VERSION 5.7 ;
  NOWIREEXTENSIONATPIN ON ;
  DIVIDERCHAR "/" ;
  BUSBITCHARS "[]" ;
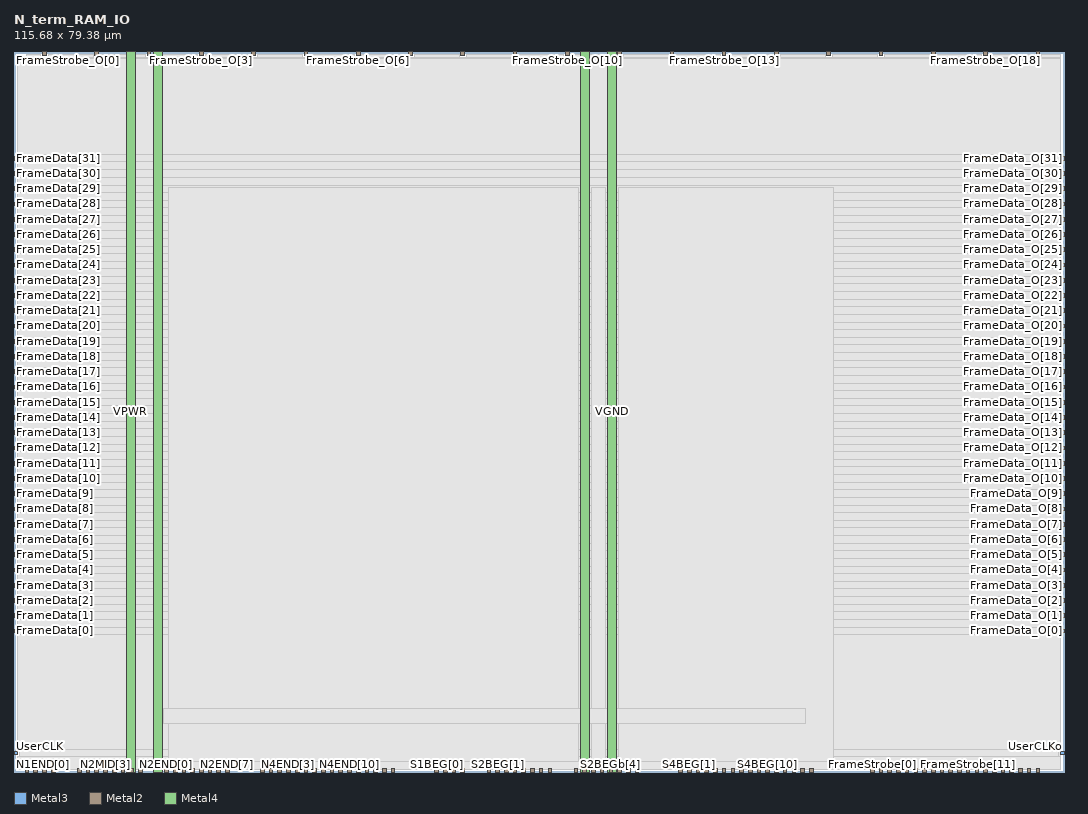
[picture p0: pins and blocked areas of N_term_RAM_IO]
MACRO N_term_RAM_IO
  CLASS BLOCK ;
  FOREIGN N_term_RAM_IO ;
  ORIGIN 0.000 0.000 ;
  SIZE 115.680 BY 79.380 ;
  PIN FrameData[0]
    DIRECTION INPUT ;
    USE SIGNAL ;
    ANTENNAGATEAREA 0.180700 ;
    PORT
      LAYER Metal3 ;
        RECT 0.000 15.340 0.400 15.740 ;
    END
  END FrameData[0]
  PIN FrameData[10]
    DIRECTION INPUT ;
    USE SIGNAL ;
    ANTENNAGATEAREA 0.180700 ;
    PORT
      LAYER Metal3 ;
        RECT 0.000 32.140 0.400 32.540 ;
    END
  END FrameData[10]
  PIN FrameData[11]
    DIRECTION INPUT ;
    USE SIGNAL ;
    ANTENNAGATEAREA 0.180700 ;
    PORT
      LAYER Metal3 ;
        RECT 0.000 33.820 0.400 34.220 ;
    END
  END FrameData[11]
  PIN FrameData[12]
    DIRECTION INPUT ;
    USE SIGNAL ;
    ANTENNAGATEAREA 0.180700 ;
    PORT
      LAYER Metal3 ;
        RECT 0.000 35.500 0.400 35.900 ;
    END
  END FrameData[12]
  PIN FrameData[13]
    DIRECTION INPUT ;
    USE SIGNAL ;
    ANTENNAGATEAREA 0.180700 ;
    PORT
      LAYER Metal3 ;
        RECT 0.000 37.180 0.400 37.580 ;
    END
  END FrameData[13]
  PIN FrameData[14]
    DIRECTION INPUT ;
    USE SIGNAL ;
    ANTENNAGATEAREA 0.180700 ;
    PORT
      LAYER Metal3 ;
        RECT 0.000 38.860 0.400 39.260 ;
    END
  END FrameData[14]
  PIN FrameData[15]
    DIRECTION INPUT ;
    USE SIGNAL ;
    ANTENNAGATEAREA 0.180700 ;
    PORT
      LAYER Metal3 ;
        RECT 0.000 40.540 0.400 40.940 ;
    END
  END FrameData[15]
  PIN FrameData[16]
    DIRECTION INPUT ;
    USE SIGNAL ;
    ANTENNAGATEAREA 0.180700 ;
    PORT
      LAYER Metal3 ;
        RECT 0.000 42.220 0.400 42.620 ;
    END
  END FrameData[16]
  PIN FrameData[17]
    DIRECTION INPUT ;
    USE SIGNAL ;
    ANTENNAGATEAREA 0.180700 ;
    PORT
      LAYER Metal3 ;
        RECT 0.000 43.900 0.400 44.300 ;
    END
  END FrameData[17]
  PIN FrameData[18]
    DIRECTION INPUT ;
    USE SIGNAL ;
    ANTENNAGATEAREA 0.180700 ;
    PORT
      LAYER Metal3 ;
        RECT 0.000 45.580 0.400 45.980 ;
    END
  END FrameData[18]
  PIN FrameData[19]
    DIRECTION INPUT ;
    USE SIGNAL ;
    ANTENNAGATEAREA 0.180700 ;
    PORT
      LAYER Metal3 ;
        RECT 0.000 47.260 0.400 47.660 ;
    END
  END FrameData[19]
  PIN FrameData[1]
    DIRECTION INPUT ;
    USE SIGNAL ;
    ANTENNAGATEAREA 0.180700 ;
    PORT
      LAYER Metal3 ;
        RECT 0.000 17.020 0.400 17.420 ;
    END
  END FrameData[1]
  PIN FrameData[20]
    DIRECTION INPUT ;
    USE SIGNAL ;
    ANTENNAGATEAREA 0.180700 ;
    PORT
      LAYER Metal3 ;
        RECT 0.000 48.940 0.400 49.340 ;
    END
  END FrameData[20]
  PIN FrameData[21]
    DIRECTION INPUT ;
    USE SIGNAL ;
    ANTENNAGATEAREA 0.180700 ;
    PORT
      LAYER Metal3 ;
        RECT 0.000 50.620 0.400 51.020 ;
    END
  END FrameData[21]
  PIN FrameData[22]
    DIRECTION INPUT ;
    USE SIGNAL ;
    ANTENNAGATEAREA 0.180700 ;
    PORT
      LAYER Metal3 ;
        RECT 0.000 52.300 0.400 52.700 ;
    END
  END FrameData[22]
  PIN FrameData[23]
    DIRECTION INPUT ;
    USE SIGNAL ;
    ANTENNAGATEAREA 0.180700 ;
    PORT
      LAYER Metal3 ;
        RECT 0.000 53.980 0.400 54.380 ;
    END
  END FrameData[23]
  PIN FrameData[24]
    DIRECTION INPUT ;
    USE SIGNAL ;
    ANTENNAGATEAREA 0.180700 ;
    PORT
      LAYER Metal3 ;
        RECT 0.000 55.660 0.400 56.060 ;
    END
  END FrameData[24]
  PIN FrameData[25]
    DIRECTION INPUT ;
    USE SIGNAL ;
    ANTENNAGATEAREA 0.180700 ;
    PORT
      LAYER Metal3 ;
        RECT 0.000 57.340 0.400 57.740 ;
    END
  END FrameData[25]
  PIN FrameData[26]
    DIRECTION INPUT ;
    USE SIGNAL ;
    ANTENNAGATEAREA 0.180700 ;
    PORT
      LAYER Metal3 ;
        RECT 0.000 59.020 0.400 59.420 ;
    END
  END FrameData[26]
  PIN FrameData[27]
    DIRECTION INPUT ;
    USE SIGNAL ;
    ANTENNAGATEAREA 0.180700 ;
    PORT
      LAYER Metal3 ;
        RECT 0.000 60.700 0.400 61.100 ;
    END
  END FrameData[27]
  PIN FrameData[28]
    DIRECTION INPUT ;
    USE SIGNAL ;
    ANTENNAGATEAREA 0.180700 ;
    PORT
      LAYER Metal3 ;
        RECT 0.000 62.380 0.400 62.780 ;
    END
  END FrameData[28]
  PIN FrameData[29]
    DIRECTION INPUT ;
    USE SIGNAL ;
    ANTENNAGATEAREA 0.180700 ;
    PORT
      LAYER Metal3 ;
        RECT 0.000 64.060 0.400 64.460 ;
    END
  END FrameData[29]
  PIN FrameData[2]
    DIRECTION INPUT ;
    USE SIGNAL ;
    ANTENNAGATEAREA 0.180700 ;
    PORT
      LAYER Metal3 ;
        RECT 0.000 18.700 0.400 19.100 ;
    END
  END FrameData[2]
  PIN FrameData[30]
    DIRECTION INPUT ;
    USE SIGNAL ;
    ANTENNAGATEAREA 0.180700 ;
    PORT
      LAYER Metal3 ;
        RECT 0.000 65.740 0.400 66.140 ;
    END
  END FrameData[30]
  PIN FrameData[31]
    DIRECTION INPUT ;
    USE SIGNAL ;
    ANTENNAGATEAREA 0.180700 ;
    PORT
      LAYER Metal3 ;
        RECT 0.000 67.420 0.400 67.820 ;
    END
  END FrameData[31]
  PIN FrameData[3]
    DIRECTION INPUT ;
    USE SIGNAL ;
    ANTENNAGATEAREA 0.180700 ;
    PORT
      LAYER Metal3 ;
        RECT 0.000 20.380 0.400 20.780 ;
    END
  END FrameData[3]
  PIN FrameData[4]
    DIRECTION INPUT ;
    USE SIGNAL ;
    ANTENNAGATEAREA 0.180700 ;
    PORT
      LAYER Metal3 ;
        RECT 0.000 22.060 0.400 22.460 ;
    END
  END FrameData[4]
  PIN FrameData[5]
    DIRECTION INPUT ;
    USE SIGNAL ;
    ANTENNAGATEAREA 0.180700 ;
    PORT
      LAYER Metal3 ;
        RECT 0.000 23.740 0.400 24.140 ;
    END
  END FrameData[5]
  PIN FrameData[6]
    DIRECTION INPUT ;
    USE SIGNAL ;
    ANTENNAGATEAREA 0.180700 ;
    PORT
      LAYER Metal3 ;
        RECT 0.000 25.420 0.400 25.820 ;
    END
  END FrameData[6]
  PIN FrameData[7]
    DIRECTION INPUT ;
    USE SIGNAL ;
    ANTENNAGATEAREA 0.180700 ;
    PORT
      LAYER Metal3 ;
        RECT 0.000 27.100 0.400 27.500 ;
    END
  END FrameData[7]
  PIN FrameData[8]
    DIRECTION INPUT ;
    USE SIGNAL ;
    ANTENNAGATEAREA 0.180700 ;
    PORT
      LAYER Metal3 ;
        RECT 0.000 28.780 0.400 29.180 ;
    END
  END FrameData[8]
  PIN FrameData[9]
    DIRECTION INPUT ;
    USE SIGNAL ;
    ANTENNAGATEAREA 0.180700 ;
    PORT
      LAYER Metal3 ;
        RECT 0.000 30.460 0.400 30.860 ;
    END
  END FrameData[9]
  PIN FrameData_O[0]
    DIRECTION OUTPUT ;
    USE SIGNAL ;
    ANTENNADIFFAREA 2.724000 ;
    PORT
      LAYER Metal3 ;
        RECT 115.280 15.340 115.680 15.740 ;
    END
  END FrameData_O[0]
  PIN FrameData_O[10]
    DIRECTION OUTPUT ;
    USE SIGNAL ;
    ANTENNADIFFAREA 2.724000 ;
    PORT
      LAYER Metal3 ;
        RECT 115.280 32.140 115.680 32.540 ;
    END
  END FrameData_O[10]
  PIN FrameData_O[11]
    DIRECTION OUTPUT ;
    USE SIGNAL ;
    ANTENNADIFFAREA 2.724000 ;
    PORT
      LAYER Metal3 ;
        RECT 115.280 33.820 115.680 34.220 ;
    END
  END FrameData_O[11]
  PIN FrameData_O[12]
    DIRECTION OUTPUT ;
    USE SIGNAL ;
    ANTENNADIFFAREA 2.724000 ;
    PORT
      LAYER Metal3 ;
        RECT 115.280 35.500 115.680 35.900 ;
    END
  END FrameData_O[12]
  PIN FrameData_O[13]
    DIRECTION OUTPUT ;
    USE SIGNAL ;
    ANTENNADIFFAREA 2.724000 ;
    PORT
      LAYER Metal3 ;
        RECT 115.280 37.180 115.680 37.580 ;
    END
  END FrameData_O[13]
  PIN FrameData_O[14]
    DIRECTION OUTPUT ;
    USE SIGNAL ;
    ANTENNADIFFAREA 2.724000 ;
    PORT
      LAYER Metal3 ;
        RECT 115.280 38.860 115.680 39.260 ;
    END
  END FrameData_O[14]
  PIN FrameData_O[15]
    DIRECTION OUTPUT ;
    USE SIGNAL ;
    ANTENNADIFFAREA 2.724000 ;
    PORT
      LAYER Metal3 ;
        RECT 115.280 40.540 115.680 40.940 ;
    END
  END FrameData_O[15]
  PIN FrameData_O[16]
    DIRECTION OUTPUT ;
    USE SIGNAL ;
    ANTENNADIFFAREA 2.724000 ;
    PORT
      LAYER Metal3 ;
        RECT 115.280 42.220 115.680 42.620 ;
    END
  END FrameData_O[16]
  PIN FrameData_O[17]
    DIRECTION OUTPUT ;
    USE SIGNAL ;
    ANTENNADIFFAREA 2.724000 ;
    PORT
      LAYER Metal3 ;
        RECT 115.280 43.900 115.680 44.300 ;
    END
  END FrameData_O[17]
  PIN FrameData_O[18]
    DIRECTION OUTPUT ;
    USE SIGNAL ;
    ANTENNADIFFAREA 2.724000 ;
    PORT
      LAYER Metal3 ;
        RECT 115.280 45.580 115.680 45.980 ;
    END
  END FrameData_O[18]
  PIN FrameData_O[19]
    DIRECTION OUTPUT ;
    USE SIGNAL ;
    ANTENNADIFFAREA 2.724000 ;
    PORT
      LAYER Metal3 ;
        RECT 115.280 47.260 115.680 47.660 ;
    END
  END FrameData_O[19]
  PIN FrameData_O[1]
    DIRECTION OUTPUT ;
    USE SIGNAL ;
    ANTENNADIFFAREA 2.724000 ;
    PORT
      LAYER Metal3 ;
        RECT 115.280 17.020 115.680 17.420 ;
    END
  END FrameData_O[1]
  PIN FrameData_O[20]
    DIRECTION OUTPUT ;
    USE SIGNAL ;
    ANTENNADIFFAREA 2.724000 ;
    PORT
      LAYER Metal3 ;
        RECT 115.280 48.940 115.680 49.340 ;
    END
  END FrameData_O[20]
  PIN FrameData_O[21]
    DIRECTION OUTPUT ;
    USE SIGNAL ;
    ANTENNADIFFAREA 2.724000 ;
    PORT
      LAYER Metal3 ;
        RECT 115.280 50.620 115.680 51.020 ;
    END
  END FrameData_O[21]
  PIN FrameData_O[22]
    DIRECTION OUTPUT ;
    USE SIGNAL ;
    ANTENNADIFFAREA 2.724000 ;
    PORT
      LAYER Metal3 ;
        RECT 115.280 52.300 115.680 52.700 ;
    END
  END FrameData_O[22]
  PIN FrameData_O[23]
    DIRECTION OUTPUT ;
    USE SIGNAL ;
    ANTENNADIFFAREA 2.724000 ;
    PORT
      LAYER Metal3 ;
        RECT 115.280 53.980 115.680 54.380 ;
    END
  END FrameData_O[23]
  PIN FrameData_O[24]
    DIRECTION OUTPUT ;
    USE SIGNAL ;
    ANTENNADIFFAREA 2.724000 ;
    PORT
      LAYER Metal3 ;
        RECT 115.280 55.660 115.680 56.060 ;
    END
  END FrameData_O[24]
  PIN FrameData_O[25]
    DIRECTION OUTPUT ;
    USE SIGNAL ;
    ANTENNADIFFAREA 2.724000 ;
    PORT
      LAYER Metal3 ;
        RECT 115.280 57.340 115.680 57.740 ;
    END
  END FrameData_O[25]
  PIN FrameData_O[26]
    DIRECTION OUTPUT ;
    USE SIGNAL ;
    ANTENNADIFFAREA 2.724000 ;
    PORT
      LAYER Metal3 ;
        RECT 115.280 59.020 115.680 59.420 ;
    END
  END FrameData_O[26]
  PIN FrameData_O[27]
    DIRECTION OUTPUT ;
    USE SIGNAL ;
    ANTENNADIFFAREA 2.724000 ;
    PORT
      LAYER Metal3 ;
        RECT 115.280 60.700 115.680 61.100 ;
    END
  END FrameData_O[27]
  PIN FrameData_O[28]
    DIRECTION OUTPUT ;
    USE SIGNAL ;
    ANTENNADIFFAREA 2.724000 ;
    PORT
      LAYER Metal3 ;
        RECT 115.280 62.380 115.680 62.780 ;
    END
  END FrameData_O[28]
  PIN FrameData_O[29]
    DIRECTION OUTPUT ;
    USE SIGNAL ;
    ANTENNADIFFAREA 2.724000 ;
    PORT
      LAYER Metal3 ;
        RECT 115.280 64.060 115.680 64.460 ;
    END
  END FrameData_O[29]
  PIN FrameData_O[2]
    DIRECTION OUTPUT ;
    USE SIGNAL ;
    ANTENNADIFFAREA 2.724000 ;
    PORT
      LAYER Metal3 ;
        RECT 115.280 18.700 115.680 19.100 ;
    END
  END FrameData_O[2]
  PIN FrameData_O[30]
    DIRECTION OUTPUT ;
    USE SIGNAL ;
    ANTENNADIFFAREA 2.724000 ;
    PORT
      LAYER Metal3 ;
        RECT 115.280 65.740 115.680 66.140 ;
    END
  END FrameData_O[30]
  PIN FrameData_O[31]
    DIRECTION OUTPUT ;
    USE SIGNAL ;
    ANTENNADIFFAREA 2.724000 ;
    PORT
      LAYER Metal3 ;
        RECT 115.280 67.420 115.680 67.820 ;
    END
  END FrameData_O[31]
  PIN FrameData_O[3]
    DIRECTION OUTPUT ;
    USE SIGNAL ;
    ANTENNADIFFAREA 2.724000 ;
    PORT
      LAYER Metal3 ;
        RECT 115.280 20.380 115.680 20.780 ;
    END
  END FrameData_O[3]
  PIN FrameData_O[4]
    DIRECTION OUTPUT ;
    USE SIGNAL ;
    ANTENNADIFFAREA 2.724000 ;
    PORT
      LAYER Metal3 ;
        RECT 115.280 22.060 115.680 22.460 ;
    END
  END FrameData_O[4]
  PIN FrameData_O[5]
    DIRECTION OUTPUT ;
    USE SIGNAL ;
    ANTENNADIFFAREA 2.724000 ;
    PORT
      LAYER Metal3 ;
        RECT 115.280 23.740 115.680 24.140 ;
    END
  END FrameData_O[5]
  PIN FrameData_O[6]
    DIRECTION OUTPUT ;
    USE SIGNAL ;
    ANTENNADIFFAREA 2.724000 ;
    PORT
      LAYER Metal3 ;
        RECT 115.280 25.420 115.680 25.820 ;
    END
  END FrameData_O[6]
  PIN FrameData_O[7]
    DIRECTION OUTPUT ;
    USE SIGNAL ;
    ANTENNADIFFAREA 2.724000 ;
    PORT
      LAYER Metal3 ;
        RECT 115.280 27.100 115.680 27.500 ;
    END
  END FrameData_O[7]
  PIN FrameData_O[8]
    DIRECTION OUTPUT ;
    USE SIGNAL ;
    ANTENNADIFFAREA 2.724000 ;
    PORT
      LAYER Metal3 ;
        RECT 115.280 28.780 115.680 29.180 ;
    END
  END FrameData_O[8]
  PIN FrameData_O[9]
    DIRECTION OUTPUT ;
    USE SIGNAL ;
    ANTENNADIFFAREA 2.724000 ;
    PORT
      LAYER Metal3 ;
        RECT 115.280 30.460 115.680 30.860 ;
    END
  END FrameData_O[9]
  PIN FrameStrobe[0]
    DIRECTION INPUT ;
    USE SIGNAL ;
    ANTENNAGATEAREA 0.180700 ;
    PORT
      LAYER Metal2 ;
        RECT 94.360 0.000 94.760 0.400 ;
    END
  END FrameStrobe[0]
  PIN FrameStrobe[10]
    DIRECTION INPUT ;
    USE SIGNAL ;
    ANTENNAGATEAREA 0.180700 ;
    PORT
      LAYER Metal2 ;
        RECT 103.960 0.000 104.360 0.400 ;
    END
  END FrameStrobe[10]
  PIN FrameStrobe[11]
    DIRECTION INPUT ;
    USE SIGNAL ;
    ANTENNAGATEAREA 0.180700 ;
    PORT
      LAYER Metal2 ;
        RECT 104.920 0.000 105.320 0.400 ;
    END
  END FrameStrobe[11]
  PIN FrameStrobe[12]
    DIRECTION INPUT ;
    USE SIGNAL ;
    ANTENNAGATEAREA 0.180700 ;
    PORT
      LAYER Metal2 ;
        RECT 105.880 0.000 106.280 0.400 ;
    END
  END FrameStrobe[12]
  PIN FrameStrobe[13]
    DIRECTION INPUT ;
    USE SIGNAL ;
    ANTENNAGATEAREA 0.180700 ;
    PORT
      LAYER Metal2 ;
        RECT 106.840 0.000 107.240 0.400 ;
    END
  END FrameStrobe[13]
  PIN FrameStrobe[14]
    DIRECTION INPUT ;
    USE SIGNAL ;
    ANTENNAGATEAREA 0.180700 ;
    PORT
      LAYER Metal2 ;
        RECT 107.800 0.000 108.200 0.400 ;
    END
  END FrameStrobe[14]
  PIN FrameStrobe[15]
    DIRECTION INPUT ;
    USE SIGNAL ;
    ANTENNAGATEAREA 0.180700 ;
    PORT
      LAYER Metal2 ;
        RECT 108.760 0.000 109.160 0.400 ;
    END
  END FrameStrobe[15]
  PIN FrameStrobe[16]
    DIRECTION INPUT ;
    USE SIGNAL ;
    ANTENNAGATEAREA 0.180700 ;
    PORT
      LAYER Metal2 ;
        RECT 109.720 0.000 110.120 0.400 ;
    END
  END FrameStrobe[16]
  PIN FrameStrobe[17]
    DIRECTION INPUT ;
    USE SIGNAL ;
    ANTENNAGATEAREA 0.180700 ;
    PORT
      LAYER Metal2 ;
        RECT 110.680 0.000 111.080 0.400 ;
    END
  END FrameStrobe[17]
  PIN FrameStrobe[18]
    DIRECTION INPUT ;
    USE SIGNAL ;
    ANTENNAGATEAREA 0.180700 ;
    PORT
      LAYER Metal2 ;
        RECT 111.640 0.000 112.040 0.400 ;
    END
  END FrameStrobe[18]
  PIN FrameStrobe[19]
    DIRECTION INPUT ;
    USE SIGNAL ;
    ANTENNAGATEAREA 0.180700 ;
    PORT
      LAYER Metal2 ;
        RECT 112.600 0.000 113.000 0.400 ;
    END
  END FrameStrobe[19]
  PIN FrameStrobe[1]
    DIRECTION INPUT ;
    USE SIGNAL ;
    ANTENNAGATEAREA 0.180700 ;
    PORT
      LAYER Metal2 ;
        RECT 95.320 0.000 95.720 0.400 ;
    END
  END FrameStrobe[1]
  PIN FrameStrobe[2]
    DIRECTION INPUT ;
    USE SIGNAL ;
    ANTENNAGATEAREA 0.180700 ;
    PORT
      LAYER Metal2 ;
        RECT 96.280 0.000 96.680 0.400 ;
    END
  END FrameStrobe[2]
  PIN FrameStrobe[3]
    DIRECTION INPUT ;
    USE SIGNAL ;
    ANTENNAGATEAREA 0.180700 ;
    PORT
      LAYER Metal2 ;
        RECT 97.240 0.000 97.640 0.400 ;
    END
  END FrameStrobe[3]
  PIN FrameStrobe[4]
    DIRECTION INPUT ;
    USE SIGNAL ;
    ANTENNAGATEAREA 0.180700 ;
    PORT
      LAYER Metal2 ;
        RECT 98.200 0.000 98.600 0.400 ;
    END
  END FrameStrobe[4]
  PIN FrameStrobe[5]
    DIRECTION INPUT ;
    USE SIGNAL ;
    ANTENNAGATEAREA 0.180700 ;
    PORT
      LAYER Metal2 ;
        RECT 99.160 0.000 99.560 0.400 ;
    END
  END FrameStrobe[5]
  PIN FrameStrobe[6]
    DIRECTION INPUT ;
    USE SIGNAL ;
    ANTENNAGATEAREA 0.180700 ;
    PORT
      LAYER Metal2 ;
        RECT 100.120 0.000 100.520 0.400 ;
    END
  END FrameStrobe[6]
  PIN FrameStrobe[7]
    DIRECTION INPUT ;
    USE SIGNAL ;
    ANTENNAGATEAREA 0.180700 ;
    PORT
      LAYER Metal2 ;
        RECT 101.080 0.000 101.480 0.400 ;
    END
  END FrameStrobe[7]
  PIN FrameStrobe[8]
    DIRECTION INPUT ;
    USE SIGNAL ;
    ANTENNAGATEAREA 0.180700 ;
    PORT
      LAYER Metal2 ;
        RECT 102.040 0.000 102.440 0.400 ;
    END
  END FrameStrobe[8]
  PIN FrameStrobe[9]
    DIRECTION INPUT ;
    USE SIGNAL ;
    ANTENNAGATEAREA 0.180700 ;
    PORT
      LAYER Metal2 ;
        RECT 103.000 0.000 103.400 0.400 ;
    END
  END FrameStrobe[9]
  PIN FrameStrobe_O[0]
    DIRECTION OUTPUT ;
    USE SIGNAL ;
    ANTENNADIFFAREA 2.724000 ;
    PORT
      LAYER Metal2 ;
        RECT 3.160 78.980 3.560 79.380 ;
    END
  END FrameStrobe_O[0]
  PIN FrameStrobe_O[10]
    DIRECTION OUTPUT ;
    USE SIGNAL ;
    ANTENNADIFFAREA 2.724000 ;
    PORT
      LAYER Metal2 ;
        RECT 60.760 78.980 61.160 79.380 ;
    END
  END FrameStrobe_O[10]
  PIN FrameStrobe_O[11]
    DIRECTION OUTPUT ;
    USE SIGNAL ;
    ANTENNADIFFAREA 2.724000 ;
    PORT
      LAYER Metal2 ;
        RECT 66.520 78.980 66.920 79.380 ;
    END
  END FrameStrobe_O[11]
  PIN FrameStrobe_O[12]
    DIRECTION OUTPUT ;
    USE SIGNAL ;
    ANTENNADIFFAREA 2.724000 ;
    PORT
      LAYER Metal2 ;
        RECT 72.280 78.980 72.680 79.380 ;
    END
  END FrameStrobe_O[12]
  PIN FrameStrobe_O[13]
    DIRECTION OUTPUT ;
    USE SIGNAL ;
    ANTENNADIFFAREA 2.724000 ;
    PORT
      LAYER Metal2 ;
        RECT 78.040 78.980 78.440 79.380 ;
    END
  END FrameStrobe_O[13]
  PIN FrameStrobe_O[14]
    DIRECTION OUTPUT ;
    USE SIGNAL ;
    ANTENNADIFFAREA 2.724000 ;
    PORT
      LAYER Metal2 ;
        RECT 83.800 78.980 84.200 79.380 ;
    END
  END FrameStrobe_O[14]
  PIN FrameStrobe_O[15]
    DIRECTION OUTPUT ;
    USE SIGNAL ;
    ANTENNADIFFAREA 2.724000 ;
    PORT
      LAYER Metal2 ;
        RECT 89.560 78.980 89.960 79.380 ;
    END
  END FrameStrobe_O[15]
  PIN FrameStrobe_O[16]
    DIRECTION OUTPUT ;
    USE SIGNAL ;
    ANTENNADIFFAREA 2.724000 ;
    PORT
      LAYER Metal2 ;
        RECT 95.320 78.980 95.720 79.380 ;
    END
  END FrameStrobe_O[16]
  PIN FrameStrobe_O[17]
    DIRECTION OUTPUT ;
    USE SIGNAL ;
    ANTENNADIFFAREA 2.724000 ;
    PORT
      LAYER Metal2 ;
        RECT 101.080 78.980 101.480 79.380 ;
    END
  END FrameStrobe_O[17]
  PIN FrameStrobe_O[18]
    DIRECTION OUTPUT ;
    USE SIGNAL ;
    ANTENNADIFFAREA 2.724000 ;
    PORT
      LAYER Metal2 ;
        RECT 106.840 78.980 107.240 79.380 ;
    END
  END FrameStrobe_O[18]
  PIN FrameStrobe_O[19]
    DIRECTION OUTPUT ;
    USE SIGNAL ;
    ANTENNADIFFAREA 2.724000 ;
    PORT
      LAYER Metal2 ;
        RECT 112.600 78.980 113.000 79.380 ;
    END
  END FrameStrobe_O[19]
  PIN FrameStrobe_O[1]
    DIRECTION OUTPUT ;
    USE SIGNAL ;
    ANTENNADIFFAREA 2.724000 ;
    PORT
      LAYER Metal2 ;
        RECT 8.920 78.980 9.320 79.380 ;
    END
  END FrameStrobe_O[1]
  PIN FrameStrobe_O[2]
    DIRECTION OUTPUT ;
    USE SIGNAL ;
    ANTENNADIFFAREA 2.724000 ;
    PORT
      LAYER Metal2 ;
        RECT 14.680 78.980 15.080 79.380 ;
    END
  END FrameStrobe_O[2]
  PIN FrameStrobe_O[3]
    DIRECTION OUTPUT ;
    USE SIGNAL ;
    ANTENNADIFFAREA 2.724000 ;
    PORT
      LAYER Metal2 ;
        RECT 20.440 78.980 20.840 79.380 ;
    END
  END FrameStrobe_O[3]
  PIN FrameStrobe_O[4]
    DIRECTION OUTPUT ;
    USE SIGNAL ;
    ANTENNADIFFAREA 2.724000 ;
    PORT
      LAYER Metal2 ;
        RECT 26.200 78.980 26.600 79.380 ;
    END
  END FrameStrobe_O[4]
  PIN FrameStrobe_O[5]
    DIRECTION OUTPUT ;
    USE SIGNAL ;
    ANTENNADIFFAREA 2.724000 ;
    PORT
      LAYER Metal2 ;
        RECT 31.960 78.980 32.360 79.380 ;
    END
  END FrameStrobe_O[5]
  PIN FrameStrobe_O[6]
    DIRECTION OUTPUT ;
    USE SIGNAL ;
    ANTENNADIFFAREA 2.724000 ;
    PORT
      LAYER Metal2 ;
        RECT 37.720 78.980 38.120 79.380 ;
    END
  END FrameStrobe_O[6]
  PIN FrameStrobe_O[7]
    DIRECTION OUTPUT ;
    USE SIGNAL ;
    ANTENNADIFFAREA 2.724000 ;
    PORT
      LAYER Metal2 ;
        RECT 43.480 78.980 43.880 79.380 ;
    END
  END FrameStrobe_O[7]
  PIN FrameStrobe_O[8]
    DIRECTION OUTPUT ;
    USE SIGNAL ;
    ANTENNADIFFAREA 2.724000 ;
    PORT
      LAYER Metal2 ;
        RECT 49.240 78.980 49.640 79.380 ;
    END
  END FrameStrobe_O[8]
  PIN FrameStrobe_O[9]
    DIRECTION OUTPUT ;
    USE SIGNAL ;
    ANTENNADIFFAREA 2.724000 ;
    PORT
      LAYER Metal2 ;
        RECT 55.000 78.980 55.400 79.380 ;
    END
  END FrameStrobe_O[9]
  PIN N1END[0]
    DIRECTION INPUT ;
    USE SIGNAL ;
    ANTENNAGATEAREA 0.180700 ;
    PORT
      LAYER Metal2 ;
        RECT 1.240 0.000 1.640 0.400 ;
    END
  END N1END[0]
  PIN N1END[1]
    DIRECTION INPUT ;
    USE SIGNAL ;
    ANTENNAGATEAREA 0.180700 ;
    PORT
      LAYER Metal2 ;
        RECT 2.200 0.000 2.600 0.400 ;
    END
  END N1END[1]
  PIN N1END[2]
    DIRECTION INPUT ;
    USE SIGNAL ;
    ANTENNAGATEAREA 0.180700 ;
    PORT
      LAYER Metal2 ;
        RECT 3.160 0.000 3.560 0.400 ;
    END
  END N1END[2]
  PIN N1END[3]
    DIRECTION INPUT ;
    USE SIGNAL ;
    ANTENNAGATEAREA 0.180700 ;
    PORT
      LAYER Metal2 ;
        RECT 4.120 0.000 4.520 0.400 ;
    END
  END N1END[3]
  PIN N2END[0]
    DIRECTION INPUT ;
    USE SIGNAL ;
    ANTENNAGATEAREA 0.180700 ;
    PORT
      LAYER Metal2 ;
        RECT 16.600 0.000 17.000 0.400 ;
    END
  END N2END[0]
  PIN N2END[1]
    DIRECTION INPUT ;
    USE SIGNAL ;
    ANTENNAGATEAREA 0.180700 ;
    PORT
      LAYER Metal2 ;
        RECT 17.560 0.000 17.960 0.400 ;
    END
  END N2END[1]
  PIN N2END[2]
    DIRECTION INPUT ;
    USE SIGNAL ;
    ANTENNAGATEAREA 0.180700 ;
    PORT
      LAYER Metal2 ;
        RECT 18.520 0.000 18.920 0.400 ;
    END
  END N2END[2]
  PIN N2END[3]
    DIRECTION INPUT ;
    USE SIGNAL ;
    ANTENNAGATEAREA 0.180700 ;
    PORT
      LAYER Metal2 ;
        RECT 19.480 0.000 19.880 0.400 ;
    END
  END N2END[3]
  PIN N2END[4]
    DIRECTION INPUT ;
    USE SIGNAL ;
    ANTENNAGATEAREA 0.180700 ;
    PORT
      LAYER Metal2 ;
        RECT 20.440 0.000 20.840 0.400 ;
    END
  END N2END[4]
  PIN N2END[5]
    DIRECTION INPUT ;
    USE SIGNAL ;
    ANTENNAGATEAREA 0.180700 ;
    PORT
      LAYER Metal2 ;
        RECT 21.400 0.000 21.800 0.400 ;
    END
  END N2END[5]
  PIN N2END[6]
    DIRECTION INPUT ;
    USE SIGNAL ;
    ANTENNAGATEAREA 0.180700 ;
    PORT
      LAYER Metal2 ;
        RECT 22.360 0.000 22.760 0.400 ;
    END
  END N2END[6]
  PIN N2END[7]
    DIRECTION INPUT ;
    USE SIGNAL ;
    ANTENNAGATEAREA 0.180700 ;
    PORT
      LAYER Metal2 ;
        RECT 23.320 0.000 23.720 0.400 ;
    END
  END N2END[7]
  PIN N2MID[0]
    DIRECTION INPUT ;
    USE SIGNAL ;
    ANTENNAGATEAREA 0.180700 ;
    PORT
      LAYER Metal2 ;
        RECT 7.000 0.000 7.400 0.400 ;
    END
  END N2MID[0]
  PIN N2MID[1]
    DIRECTION INPUT ;
    USE SIGNAL ;
    ANTENNAGATEAREA 0.180700 ;
    PORT
      LAYER Metal2 ;
        RECT 7.960 0.000 8.360 0.400 ;
    END
  END N2MID[1]
  PIN N2MID[2]
    DIRECTION INPUT ;
    USE SIGNAL ;
    ANTENNAGATEAREA 0.180700 ;
    PORT
      LAYER Metal2 ;
        RECT 8.920 0.000 9.320 0.400 ;
    END
  END N2MID[2]
  PIN N2MID[3]
    DIRECTION INPUT ;
    USE SIGNAL ;
    ANTENNAGATEAREA 0.180700 ;
    PORT
      LAYER Metal2 ;
        RECT 9.880 0.000 10.280 0.400 ;
    END
  END N2MID[3]
  PIN N2MID[4]
    DIRECTION INPUT ;
    USE SIGNAL ;
    ANTENNAGATEAREA 0.180700 ;
    PORT
      LAYER Metal2 ;
        RECT 10.840 0.000 11.240 0.400 ;
    END
  END N2MID[4]
  PIN N2MID[5]
    DIRECTION INPUT ;
    USE SIGNAL ;
    ANTENNAGATEAREA 0.180700 ;
    PORT
      LAYER Metal2 ;
        RECT 11.800 0.000 12.200 0.400 ;
    END
  END N2MID[5]
  PIN N2MID[6]
    DIRECTION INPUT ;
    USE SIGNAL ;
    ANTENNAGATEAREA 0.180700 ;
    PORT
      LAYER Metal2 ;
        RECT 12.760 0.000 13.160 0.400 ;
    END
  END N2MID[6]
  PIN N2MID[7]
    DIRECTION INPUT ;
    USE SIGNAL ;
    ANTENNAGATEAREA 0.180700 ;
    PORT
      LAYER Metal2 ;
        RECT 13.720 0.000 14.120 0.400 ;
    END
  END N2MID[7]
  PIN N4END[0]
    DIRECTION INPUT ;
    USE SIGNAL ;
    ANTENNAGATEAREA 0.180700 ;
    PORT
      LAYER Metal2 ;
        RECT 27.160 0.000 27.560 0.400 ;
    END
  END N4END[0]
  PIN N4END[10]
    DIRECTION INPUT ;
    USE SIGNAL ;
    ANTENNAGATEAREA 0.180700 ;
    PORT
      LAYER Metal2 ;
        RECT 36.760 0.000 37.160 0.400 ;
    END
  END N4END[10]
  PIN N4END[11]
    DIRECTION INPUT ;
    USE SIGNAL ;
    ANTENNAGATEAREA 0.180700 ;
    PORT
      LAYER Metal2 ;
        RECT 37.720 0.000 38.120 0.400 ;
    END
  END N4END[11]
  PIN N4END[12]
    DIRECTION INPUT ;
    USE SIGNAL ;
    ANTENNAGATEAREA 0.180700 ;
    PORT
      LAYER Metal2 ;
        RECT 38.680 0.000 39.080 0.400 ;
    END
  END N4END[12]
  PIN N4END[13]
    DIRECTION INPUT ;
    USE SIGNAL ;
    ANTENNAGATEAREA 0.180700 ;
    PORT
      LAYER Metal2 ;
        RECT 39.640 0.000 40.040 0.400 ;
    END
  END N4END[13]
  PIN N4END[14]
    DIRECTION INPUT ;
    USE SIGNAL ;
    ANTENNAGATEAREA 0.180700 ;
    PORT
      LAYER Metal2 ;
        RECT 40.600 0.000 41.000 0.400 ;
    END
  END N4END[14]
  PIN N4END[15]
    DIRECTION INPUT ;
    USE SIGNAL ;
    ANTENNAGATEAREA 0.180700 ;
    PORT
      LAYER Metal2 ;
        RECT 41.560 0.000 41.960 0.400 ;
    END
  END N4END[15]
  PIN N4END[1]
    DIRECTION INPUT ;
    USE SIGNAL ;
    ANTENNAGATEAREA 0.180700 ;
    PORT
      LAYER Metal2 ;
        RECT 28.120 0.000 28.520 0.400 ;
    END
  END N4END[1]
  PIN N4END[2]
    DIRECTION INPUT ;
    USE SIGNAL ;
    ANTENNAGATEAREA 0.180700 ;
    PORT
      LAYER Metal2 ;
        RECT 29.080 0.000 29.480 0.400 ;
    END
  END N4END[2]
  PIN N4END[3]
    DIRECTION INPUT ;
    USE SIGNAL ;
    ANTENNAGATEAREA 0.180700 ;
    PORT
      LAYER Metal2 ;
        RECT 30.040 0.000 30.440 0.400 ;
    END
  END N4END[3]
  PIN N4END[4]
    DIRECTION INPUT ;
    USE SIGNAL ;
    ANTENNAGATEAREA 0.180700 ;
    PORT
      LAYER Metal2 ;
        RECT 31.000 0.000 31.400 0.400 ;
    END
  END N4END[4]
  PIN N4END[5]
    DIRECTION INPUT ;
    USE SIGNAL ;
    ANTENNAGATEAREA 0.180700 ;
    PORT
      LAYER Metal2 ;
        RECT 31.960 0.000 32.360 0.400 ;
    END
  END N4END[5]
  PIN N4END[6]
    DIRECTION INPUT ;
    USE SIGNAL ;
    ANTENNAGATEAREA 0.180700 ;
    PORT
      LAYER Metal2 ;
        RECT 32.920 0.000 33.320 0.400 ;
    END
  END N4END[6]
  PIN N4END[7]
    DIRECTION INPUT ;
    USE SIGNAL ;
    ANTENNAGATEAREA 0.180700 ;
    PORT
      LAYER Metal2 ;
        RECT 33.880 0.000 34.280 0.400 ;
    END
  END N4END[7]
  PIN N4END[8]
    DIRECTION INPUT ;
    USE SIGNAL ;
    ANTENNAGATEAREA 0.180700 ;
    PORT
      LAYER Metal2 ;
        RECT 34.840 0.000 35.240 0.400 ;
    END
  END N4END[8]
  PIN N4END[9]
    DIRECTION INPUT ;
    USE SIGNAL ;
    ANTENNAGATEAREA 0.180700 ;
    PORT
      LAYER Metal2 ;
        RECT 35.800 0.000 36.200 0.400 ;
    END
  END N4END[9]
  PIN S1BEG[0]
    DIRECTION OUTPUT ;
    USE SIGNAL ;
    ANTENNADIFFAREA 2.724000 ;
    PORT
      LAYER Metal2 ;
        RECT 46.360 0.000 46.760 0.400 ;
    END
  END S1BEG[0]
  PIN S1BEG[1]
    DIRECTION OUTPUT ;
    USE SIGNAL ;
    ANTENNADIFFAREA 2.724000 ;
    PORT
      LAYER Metal2 ;
        RECT 47.320 0.000 47.720 0.400 ;
    END
  END S1BEG[1]
  PIN S1BEG[2]
    DIRECTION OUTPUT ;
    USE SIGNAL ;
    ANTENNADIFFAREA 2.724000 ;
    PORT
      LAYER Metal2 ;
        RECT 48.280 0.000 48.680 0.400 ;
    END
  END S1BEG[2]
  PIN S1BEG[3]
    DIRECTION OUTPUT ;
    USE SIGNAL ;
    ANTENNADIFFAREA 2.724000 ;
    PORT
      LAYER Metal2 ;
        RECT 49.240 0.000 49.640 0.400 ;
    END
  END S1BEG[3]
  PIN S2BEG[0]
    DIRECTION OUTPUT ;
    USE SIGNAL ;
    ANTENNADIFFAREA 2.724000 ;
    PORT
      LAYER Metal2 ;
        RECT 52.120 0.000 52.520 0.400 ;
    END
  END S2BEG[0]
  PIN S2BEG[1]
    DIRECTION OUTPUT ;
    USE SIGNAL ;
    ANTENNADIFFAREA 2.724000 ;
    PORT
      LAYER Metal2 ;
        RECT 53.080 0.000 53.480 0.400 ;
    END
  END S2BEG[1]
  PIN S2BEG[2]
    DIRECTION OUTPUT ;
    USE SIGNAL ;
    ANTENNADIFFAREA 2.724000 ;
    PORT
      LAYER Metal2 ;
        RECT 54.040 0.000 54.440 0.400 ;
    END
  END S2BEG[2]
  PIN S2BEG[3]
    DIRECTION OUTPUT ;
    USE SIGNAL ;
    ANTENNADIFFAREA 2.724000 ;
    PORT
      LAYER Metal2 ;
        RECT 55.000 0.000 55.400 0.400 ;
    END
  END S2BEG[3]
  PIN S2BEG[4]
    DIRECTION OUTPUT ;
    USE SIGNAL ;
    ANTENNADIFFAREA 2.724000 ;
    PORT
      LAYER Metal2 ;
        RECT 55.960 0.000 56.360 0.400 ;
    END
  END S2BEG[4]
  PIN S2BEG[5]
    DIRECTION OUTPUT ;
    USE SIGNAL ;
    ANTENNADIFFAREA 2.724000 ;
    PORT
      LAYER Metal2 ;
        RECT 56.920 0.000 57.320 0.400 ;
    END
  END S2BEG[5]
  PIN S2BEG[6]
    DIRECTION OUTPUT ;
    USE SIGNAL ;
    ANTENNADIFFAREA 2.724000 ;
    PORT
      LAYER Metal2 ;
        RECT 57.880 0.000 58.280 0.400 ;
    END
  END S2BEG[6]
  PIN S2BEG[7]
    DIRECTION OUTPUT ;
    USE SIGNAL ;
    ANTENNADIFFAREA 2.724000 ;
    PORT
      LAYER Metal2 ;
        RECT 58.840 0.000 59.240 0.400 ;
    END
  END S2BEG[7]
  PIN S2BEGb[0]
    DIRECTION OUTPUT ;
    USE SIGNAL ;
    ANTENNADIFFAREA 2.724000 ;
    PORT
      LAYER Metal2 ;
        RECT 61.720 0.000 62.120 0.400 ;
    END
  END S2BEGb[0]
  PIN S2BEGb[1]
    DIRECTION OUTPUT ;
    USE SIGNAL ;
    ANTENNADIFFAREA 2.724000 ;
    PORT
      LAYER Metal2 ;
        RECT 62.680 0.000 63.080 0.400 ;
    END
  END S2BEGb[1]
  PIN S2BEGb[2]
    DIRECTION OUTPUT ;
    USE SIGNAL ;
    ANTENNADIFFAREA 2.724000 ;
    PORT
      LAYER Metal2 ;
        RECT 63.640 0.000 64.040 0.400 ;
    END
  END S2BEGb[2]
  PIN S2BEGb[3]
    DIRECTION OUTPUT ;
    USE SIGNAL ;
    ANTENNADIFFAREA 2.724000 ;
    PORT
      LAYER Metal2 ;
        RECT 64.600 0.000 65.000 0.400 ;
    END
  END S2BEGb[3]
  PIN S2BEGb[4]
    DIRECTION OUTPUT ;
    USE SIGNAL ;
    ANTENNADIFFAREA 2.724000 ;
    PORT
      LAYER Metal2 ;
        RECT 65.560 0.000 65.960 0.400 ;
    END
  END S2BEGb[4]
  PIN S2BEGb[5]
    DIRECTION OUTPUT ;
    USE SIGNAL ;
    ANTENNADIFFAREA 2.724000 ;
    PORT
      LAYER Metal2 ;
        RECT 66.520 0.000 66.920 0.400 ;
    END
  END S2BEGb[5]
  PIN S2BEGb[6]
    DIRECTION OUTPUT ;
    USE SIGNAL ;
    ANTENNADIFFAREA 2.724000 ;
    PORT
      LAYER Metal2 ;
        RECT 67.480 0.000 67.880 0.400 ;
    END
  END S2BEGb[6]
  PIN S2BEGb[7]
    DIRECTION OUTPUT ;
    USE SIGNAL ;
    ANTENNADIFFAREA 2.724000 ;
    PORT
      LAYER Metal2 ;
        RECT 68.440 0.000 68.840 0.400 ;
    END
  END S2BEGb[7]
  PIN S4BEG[0]
    DIRECTION OUTPUT ;
    USE SIGNAL ;
    ANTENNADIFFAREA 2.724000 ;
    PORT
      LAYER Metal2 ;
        RECT 73.240 0.000 73.640 0.400 ;
    END
  END S4BEG[0]
  PIN S4BEG[10]
    DIRECTION OUTPUT ;
    USE SIGNAL ;
    ANTENNADIFFAREA 2.724000 ;
    PORT
      LAYER Metal2 ;
        RECT 82.840 0.000 83.240 0.400 ;
    END
  END S4BEG[10]
  PIN S4BEG[11]
    DIRECTION OUTPUT ;
    USE SIGNAL ;
    ANTENNADIFFAREA 2.724000 ;
    PORT
      LAYER Metal2 ;
        RECT 83.800 0.000 84.200 0.400 ;
    END
  END S4BEG[11]
  PIN S4BEG[12]
    DIRECTION OUTPUT ;
    USE SIGNAL ;
    ANTENNADIFFAREA 2.724000 ;
    PORT
      LAYER Metal2 ;
        RECT 84.760 0.000 85.160 0.400 ;
    END
  END S4BEG[12]
  PIN S4BEG[13]
    DIRECTION OUTPUT ;
    USE SIGNAL ;
    ANTENNADIFFAREA 2.724000 ;
    PORT
      LAYER Metal2 ;
        RECT 85.720 0.000 86.120 0.400 ;
    END
  END S4BEG[13]
  PIN S4BEG[14]
    DIRECTION OUTPUT ;
    USE SIGNAL ;
    ANTENNADIFFAREA 2.724000 ;
    PORT
      LAYER Metal2 ;
        RECT 86.680 0.000 87.080 0.400 ;
    END
  END S4BEG[14]
  PIN S4BEG[15]
    DIRECTION OUTPUT ;
    USE SIGNAL ;
    ANTENNADIFFAREA 2.724000 ;
    PORT
      LAYER Metal2 ;
        RECT 87.640 0.000 88.040 0.400 ;
    END
  END S4BEG[15]
  PIN S4BEG[1]
    DIRECTION OUTPUT ;
    USE SIGNAL ;
    ANTENNADIFFAREA 2.724000 ;
    PORT
      LAYER Metal2 ;
        RECT 74.200 0.000 74.600 0.400 ;
    END
  END S4BEG[1]
  PIN S4BEG[2]
    DIRECTION OUTPUT ;
    USE SIGNAL ;
    ANTENNADIFFAREA 2.724000 ;
    PORT
      LAYER Metal2 ;
        RECT 75.160 0.000 75.560 0.400 ;
    END
  END S4BEG[2]
  PIN S4BEG[3]
    DIRECTION OUTPUT ;
    USE SIGNAL ;
    ANTENNADIFFAREA 2.724000 ;
    PORT
      LAYER Metal2 ;
        RECT 76.120 0.000 76.520 0.400 ;
    END
  END S4BEG[3]
  PIN S4BEG[4]
    DIRECTION OUTPUT ;
    USE SIGNAL ;
    ANTENNADIFFAREA 2.724000 ;
    PORT
      LAYER Metal2 ;
        RECT 77.080 0.000 77.480 0.400 ;
    END
  END S4BEG[4]
  PIN S4BEG[5]
    DIRECTION OUTPUT ;
    USE SIGNAL ;
    ANTENNADIFFAREA 2.724000 ;
    PORT
      LAYER Metal2 ;
        RECT 78.040 0.000 78.440 0.400 ;
    END
  END S4BEG[5]
  PIN S4BEG[6]
    DIRECTION OUTPUT ;
    USE SIGNAL ;
    ANTENNADIFFAREA 2.724000 ;
    PORT
      LAYER Metal2 ;
        RECT 79.000 0.000 79.400 0.400 ;
    END
  END S4BEG[6]
  PIN S4BEG[7]
    DIRECTION OUTPUT ;
    USE SIGNAL ;
    ANTENNADIFFAREA 2.724000 ;
    PORT
      LAYER Metal2 ;
        RECT 79.960 0.000 80.360 0.400 ;
    END
  END S4BEG[7]
  PIN S4BEG[8]
    DIRECTION OUTPUT ;
    USE SIGNAL ;
    ANTENNADIFFAREA 2.724000 ;
    PORT
      LAYER Metal2 ;
        RECT 80.920 0.000 81.320 0.400 ;
    END
  END S4BEG[8]
  PIN S4BEG[9]
    DIRECTION OUTPUT ;
    USE SIGNAL ;
    ANTENNADIFFAREA 2.724000 ;
    PORT
      LAYER Metal2 ;
        RECT 81.880 0.000 82.280 0.400 ;
    END
  END S4BEG[9]
  PIN UserCLK
    DIRECTION INPUT ;
    USE SIGNAL ;
    ANTENNAGATEAREA 0.180700 ;
    PORT
      LAYER Metal3 ;
        RECT 0.000 1.900 0.400 2.300 ;
    END
  END UserCLK
  PIN UserCLKo
    DIRECTION OUTPUT ;
    USE SIGNAL ;
    ANTENNADIFFAREA 2.724000 ;
    PORT
      LAYER Metal3 ;
        RECT 115.280 1.900 115.680 2.300 ;
    END
  END UserCLKo
  PIN VGND
    DIRECTION INOUT ;
    USE GROUND ;
    PORT
      LAYER Metal4 ;
        RECT 15.380 0.000 16.380 79.380 ;
    END
    PORT
      LAYER Metal4 ;
        RECT 65.380 0.000 66.380 79.380 ;
    END
  END VGND
  PIN VPWR
    DIRECTION INOUT ;
    USE POWER ;
    PORT
      LAYER Metal4 ;
        RECT 12.380 0.000 13.380 79.380 ;
    END
    PORT
      LAYER Metal4 ;
        RECT 62.380 0.000 63.380 79.380 ;
    END
  END VPWR
  OBS
      LAYER GatPoly ;
        RECT 2.880 3.630 112.800 75.750 ;
      LAYER Metal1 ;
        RECT 2.880 3.560 112.800 75.820 ;
      LAYER Metal2 ;
        RECT 1.340 78.770 2.950 79.060 ;
        RECT 3.770 78.770 8.710 79.060 ;
        RECT 9.530 78.770 14.470 79.060 ;
        RECT 15.290 78.770 20.230 79.060 ;
        RECT 21.050 78.770 25.990 79.060 ;
        RECT 26.810 78.770 31.750 79.060 ;
        RECT 32.570 78.770 37.510 79.060 ;
        RECT 38.330 78.770 43.270 79.060 ;
        RECT 44.090 78.770 49.030 79.060 ;
        RECT 49.850 78.770 54.790 79.060 ;
        RECT 55.610 78.770 60.550 79.060 ;
        RECT 61.370 78.770 66.310 79.060 ;
        RECT 67.130 78.770 72.070 79.060 ;
        RECT 72.890 78.770 77.830 79.060 ;
        RECT 78.650 78.770 83.590 79.060 ;
        RECT 84.410 78.770 89.350 79.060 ;
        RECT 90.170 78.770 95.110 79.060 ;
        RECT 95.930 78.770 100.870 79.060 ;
        RECT 101.690 78.770 106.630 79.060 ;
        RECT 107.450 78.770 112.390 79.060 ;
        RECT 113.210 78.770 115.305 79.060 ;
        RECT 1.340 0.610 115.305 78.770 ;
        RECT 1.850 0.275 1.990 0.610 ;
        RECT 2.810 0.275 2.950 0.610 ;
        RECT 3.770 0.275 3.910 0.610 ;
        RECT 4.730 0.275 6.790 0.610 ;
        RECT 7.610 0.275 7.750 0.610 ;
        RECT 8.570 0.275 8.710 0.610 ;
        RECT 9.530 0.275 9.670 0.610 ;
        RECT 10.490 0.275 10.630 0.610 ;
        RECT 11.450 0.275 11.590 0.610 ;
        RECT 12.410 0.275 12.550 0.610 ;
        RECT 13.370 0.275 13.510 0.610 ;
        RECT 14.330 0.275 16.390 0.610 ;
        RECT 17.210 0.275 17.350 0.610 ;
        RECT 18.170 0.275 18.310 0.610 ;
        RECT 19.130 0.275 19.270 0.610 ;
        RECT 20.090 0.275 20.230 0.610 ;
        RECT 21.050 0.275 21.190 0.610 ;
        RECT 22.010 0.275 22.150 0.610 ;
        RECT 22.970 0.275 23.110 0.610 ;
        RECT 23.930 0.275 26.950 0.610 ;
        RECT 27.770 0.275 27.910 0.610 ;
        RECT 28.730 0.275 28.870 0.610 ;
        RECT 29.690 0.275 29.830 0.610 ;
        RECT 30.650 0.275 30.790 0.610 ;
        RECT 31.610 0.275 31.750 0.610 ;
        RECT 32.570 0.275 32.710 0.610 ;
        RECT 33.530 0.275 33.670 0.610 ;
        RECT 34.490 0.275 34.630 0.610 ;
        RECT 35.450 0.275 35.590 0.610 ;
        RECT 36.410 0.275 36.550 0.610 ;
        RECT 37.370 0.275 37.510 0.610 ;
        RECT 38.330 0.275 38.470 0.610 ;
        RECT 39.290 0.275 39.430 0.610 ;
        RECT 40.250 0.275 40.390 0.610 ;
        RECT 41.210 0.275 41.350 0.610 ;
        RECT 42.170 0.275 46.150 0.610 ;
        RECT 46.970 0.275 47.110 0.610 ;
        RECT 47.930 0.275 48.070 0.610 ;
        RECT 48.890 0.275 49.030 0.610 ;
        RECT 49.850 0.275 51.910 0.610 ;
        RECT 52.730 0.275 52.870 0.610 ;
        RECT 53.690 0.275 53.830 0.610 ;
        RECT 54.650 0.275 54.790 0.610 ;
        RECT 55.610 0.275 55.750 0.610 ;
        RECT 56.570 0.275 56.710 0.610 ;
        RECT 57.530 0.275 57.670 0.610 ;
        RECT 58.490 0.275 58.630 0.610 ;
        RECT 59.450 0.275 61.510 0.610 ;
        RECT 62.330 0.275 62.470 0.610 ;
        RECT 63.290 0.275 63.430 0.610 ;
        RECT 64.250 0.275 64.390 0.610 ;
        RECT 65.210 0.275 65.350 0.610 ;
        RECT 66.170 0.275 66.310 0.610 ;
        RECT 67.130 0.275 67.270 0.610 ;
        RECT 68.090 0.275 68.230 0.610 ;
        RECT 69.050 0.275 73.030 0.610 ;
        RECT 73.850 0.275 73.990 0.610 ;
        RECT 74.810 0.275 74.950 0.610 ;
        RECT 75.770 0.275 75.910 0.610 ;
        RECT 76.730 0.275 76.870 0.610 ;
        RECT 77.690 0.275 77.830 0.610 ;
        RECT 78.650 0.275 78.790 0.610 ;
        RECT 79.610 0.275 79.750 0.610 ;
        RECT 80.570 0.275 80.710 0.610 ;
        RECT 81.530 0.275 81.670 0.610 ;
        RECT 82.490 0.275 82.630 0.610 ;
        RECT 83.450 0.275 83.590 0.610 ;
        RECT 84.410 0.275 84.550 0.610 ;
        RECT 85.370 0.275 85.510 0.610 ;
        RECT 86.330 0.275 86.470 0.610 ;
        RECT 87.290 0.275 87.430 0.610 ;
        RECT 88.250 0.275 94.150 0.610 ;
        RECT 94.970 0.275 95.110 0.610 ;
        RECT 95.930 0.275 96.070 0.610 ;
        RECT 96.890 0.275 97.030 0.610 ;
        RECT 97.850 0.275 97.990 0.610 ;
        RECT 98.810 0.275 98.950 0.610 ;
        RECT 99.770 0.275 99.910 0.610 ;
        RECT 100.730 0.275 100.870 0.610 ;
        RECT 101.690 0.275 101.830 0.610 ;
        RECT 102.650 0.275 102.790 0.610 ;
        RECT 103.610 0.275 103.750 0.610 ;
        RECT 104.570 0.275 104.710 0.610 ;
        RECT 105.530 0.275 105.670 0.610 ;
        RECT 106.490 0.275 106.630 0.610 ;
        RECT 107.450 0.275 107.590 0.610 ;
        RECT 108.410 0.275 108.550 0.610 ;
        RECT 109.370 0.275 109.510 0.610 ;
        RECT 110.330 0.275 110.470 0.610 ;
        RECT 111.290 0.275 111.430 0.610 ;
        RECT 112.250 0.275 112.390 0.610 ;
        RECT 113.210 0.275 115.305 0.610 ;
      LAYER Metal3 ;
        RECT 0.400 68.030 115.345 78.640 ;
        RECT 0.610 67.210 115.070 68.030 ;
        RECT 0.400 66.350 115.345 67.210 ;
        RECT 0.610 65.530 115.070 66.350 ;
        RECT 0.400 64.670 115.345 65.530 ;
        RECT 0.610 63.850 115.070 64.670 ;
        RECT 0.400 62.990 115.345 63.850 ;
        RECT 0.610 62.170 115.070 62.990 ;
        RECT 0.400 61.310 115.345 62.170 ;
        RECT 0.610 60.490 115.070 61.310 ;
        RECT 0.400 59.630 115.345 60.490 ;
        RECT 0.610 58.810 115.070 59.630 ;
        RECT 0.400 57.950 115.345 58.810 ;
        RECT 0.610 57.130 115.070 57.950 ;
        RECT 0.400 56.270 115.345 57.130 ;
        RECT 0.610 55.450 115.070 56.270 ;
        RECT 0.400 54.590 115.345 55.450 ;
        RECT 0.610 53.770 115.070 54.590 ;
        RECT 0.400 52.910 115.345 53.770 ;
        RECT 0.610 52.090 115.070 52.910 ;
        RECT 0.400 51.230 115.345 52.090 ;
        RECT 0.610 50.410 115.070 51.230 ;
        RECT 0.400 49.550 115.345 50.410 ;
        RECT 0.610 48.730 115.070 49.550 ;
        RECT 0.400 47.870 115.345 48.730 ;
        RECT 0.610 47.050 115.070 47.870 ;
        RECT 0.400 46.190 115.345 47.050 ;
        RECT 0.610 45.370 115.070 46.190 ;
        RECT 0.400 44.510 115.345 45.370 ;
        RECT 0.610 43.690 115.070 44.510 ;
        RECT 0.400 42.830 115.345 43.690 ;
        RECT 0.610 42.010 115.070 42.830 ;
        RECT 0.400 41.150 115.345 42.010 ;
        RECT 0.610 40.330 115.070 41.150 ;
        RECT 0.400 39.470 115.345 40.330 ;
        RECT 0.610 38.650 115.070 39.470 ;
        RECT 0.400 37.790 115.345 38.650 ;
        RECT 0.610 36.970 115.070 37.790 ;
        RECT 0.400 36.110 115.345 36.970 ;
        RECT 0.610 35.290 115.070 36.110 ;
        RECT 0.400 34.430 115.345 35.290 ;
        RECT 0.610 33.610 115.070 34.430 ;
        RECT 0.400 32.750 115.345 33.610 ;
        RECT 0.610 31.930 115.070 32.750 ;
        RECT 0.400 31.070 115.345 31.930 ;
        RECT 0.610 30.250 115.070 31.070 ;
        RECT 0.400 29.390 115.345 30.250 ;
        RECT 0.610 28.570 115.070 29.390 ;
        RECT 0.400 27.710 115.345 28.570 ;
        RECT 0.610 26.890 115.070 27.710 ;
        RECT 0.400 26.030 115.345 26.890 ;
        RECT 0.610 25.210 115.070 26.030 ;
        RECT 0.400 24.350 115.345 25.210 ;
        RECT 0.610 23.530 115.070 24.350 ;
        RECT 0.400 22.670 115.345 23.530 ;
        RECT 0.610 21.850 115.070 22.670 ;
        RECT 0.400 20.990 115.345 21.850 ;
        RECT 0.610 20.170 115.070 20.990 ;
        RECT 0.400 19.310 115.345 20.170 ;
        RECT 0.610 18.490 115.070 19.310 ;
        RECT 0.400 17.630 115.345 18.490 ;
        RECT 0.610 16.810 115.070 17.630 ;
        RECT 0.400 15.950 115.345 16.810 ;
        RECT 0.610 15.130 115.070 15.950 ;
        RECT 0.400 2.510 115.345 15.130 ;
        RECT 0.610 1.690 115.070 2.510 ;
        RECT 0.400 0.320 115.345 1.690 ;
      LAYER Metal4 ;
        RECT 16.970 1.115 62.170 64.405 ;
        RECT 63.590 1.115 65.170 64.405 ;
        RECT 66.590 1.115 90.340 64.405 ;
      LAYER TopMetal1 ;
        RECT 16.460 5.380 87.220 7.020 ;
  END
END N_term_RAM_IO
END LIBRARY

